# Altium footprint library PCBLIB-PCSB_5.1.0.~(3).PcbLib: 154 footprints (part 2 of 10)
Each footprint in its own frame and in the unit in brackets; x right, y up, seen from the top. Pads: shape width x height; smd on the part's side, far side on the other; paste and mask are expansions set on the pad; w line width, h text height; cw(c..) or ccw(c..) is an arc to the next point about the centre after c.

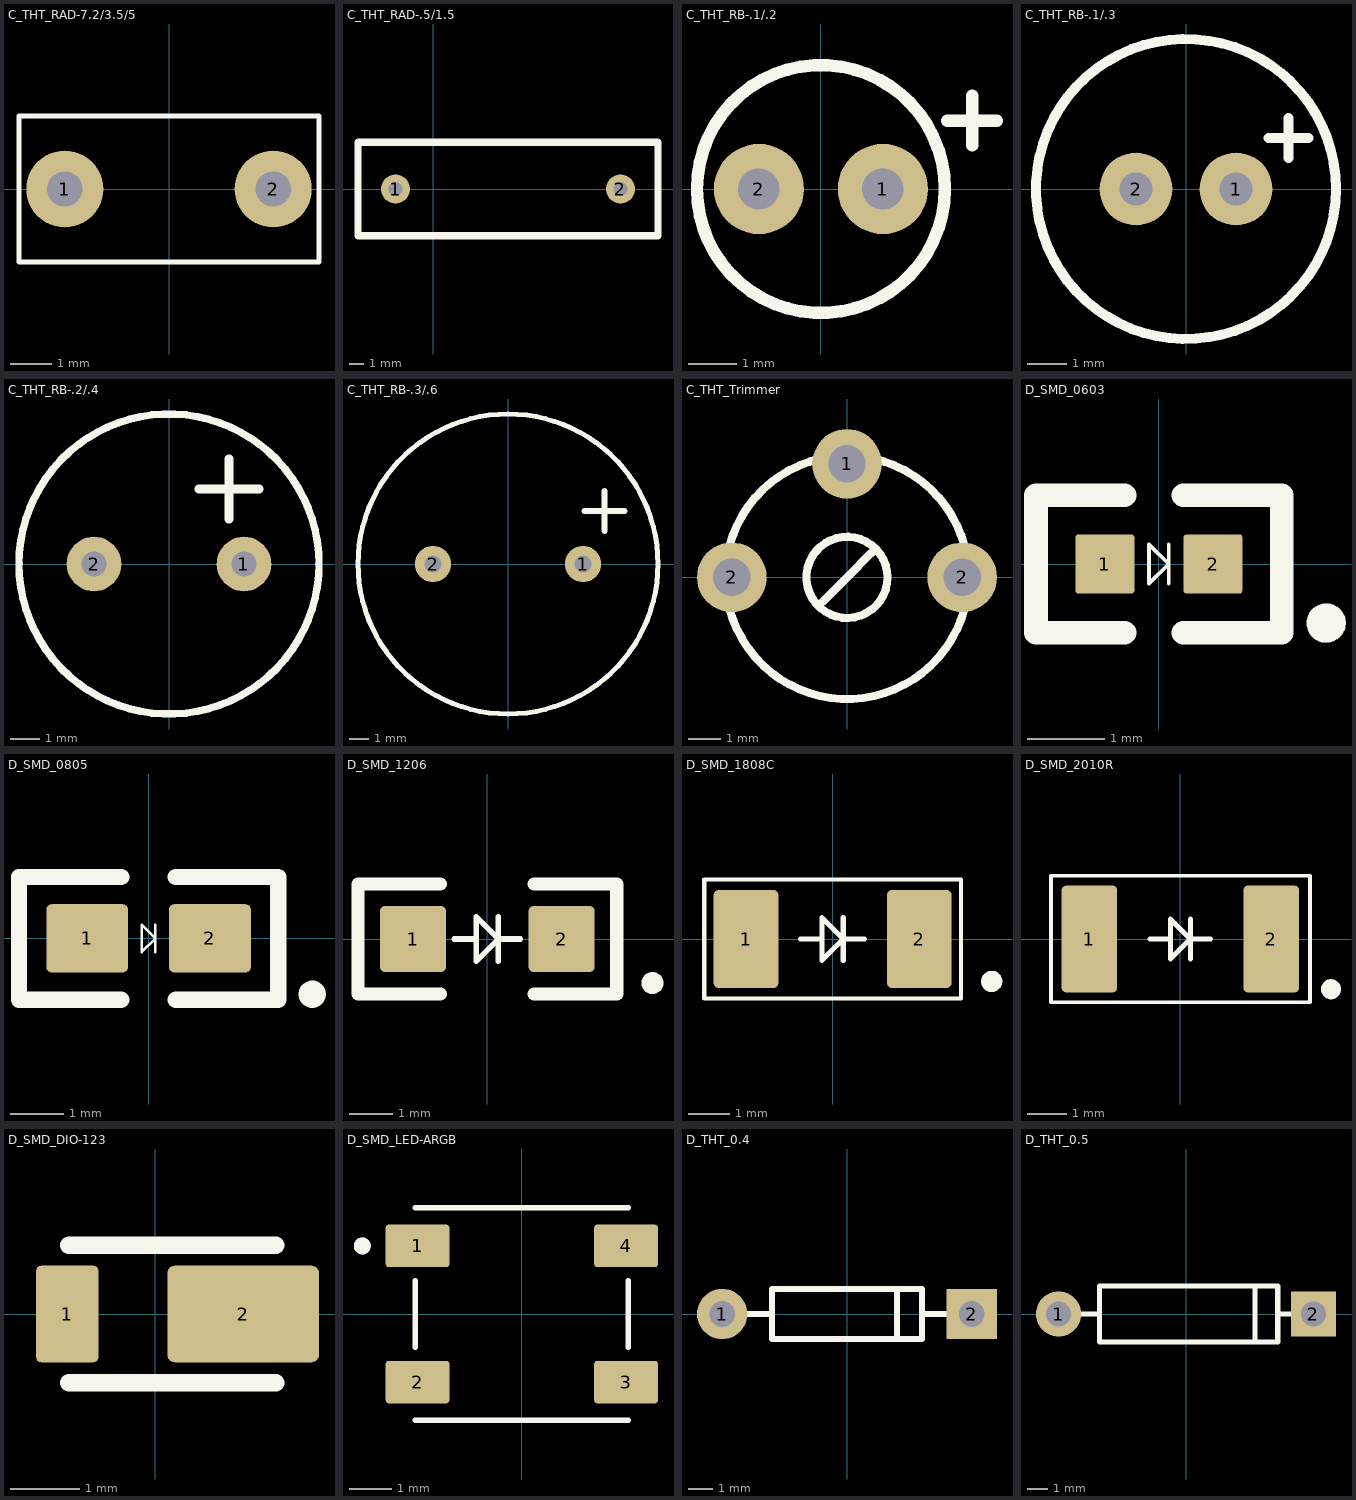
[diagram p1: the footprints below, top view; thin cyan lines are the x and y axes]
## C_THT_RAD-7.2/3.5/5 [mm] "LB-2024-04-17"
pads (2):
  round 1.85 hole 0.85: 1(-2.5,0) 2(2.5,0)
Top Overlay:
  lines w0.127: -3.6,-1.75 -3.6,1.75 3.6,1.75 3.6,-1.75 -3.6,-1.75

## C_THT_RAD-.5/1.5 [mm] "LB-2024-04-17"
pads (2):
  round 1.95 hole 0.95: 1(-2.54,0) 2(12.7,0)
Top Overlay:
  lines w0.5: -5.08,1.27 -5.08,3.175 15.24,3.175 15.24,-3.175 -5.08,-3.175 -5.08,1.595

## C_THT_RB-.1/.2 [mm] "LB-2024-04-15"
pads (2):
  round 1.85 hole 0.85: 1(1.27,0) 2(-1.27,0)
Top Overlay:
  circle w0.254: c0,0 r2.54
  lines w0.254: 2.592,1.4 3.608,1.4 ; 3.1,0.892 3.1,1.908

## C_THT_RB-.1/.3 [mm] "LB-2024-04-15"
pads (2):
  round 1.85 hole 0.85: 1(1.27,0) 2(-1.27,0)
Top Overlay:
  circle w0.254: c0,0 r3.81
  lines w0.254: 2.092,1.3 3.108,1.3 ; 2.6,0.792 2.6,1.808

## C_THT_RB-.2/.4 [mm] "LB-2024-04-16"
pads (2):
  round 1.85 hole 0.85: 1(2.54,0) 2(-2.54,0)
Top Overlay:
  circle w0.254: c0,0 r5.08
  lines w0.305: 1.016,2.54 3.048,2.54 ; 2.032,1.524 2.032,3.556

## C_THT_RB-.3/.6 [mm] "LB-2024-04-15"
pads (2):
  round 1.85 hole 0.85: 1(3.81,0) 2(-3.81,0)
Top Overlay:
  circle w0.254: c0,0 r7.62
  lines w0.305: 3.884,2.7 4.392,2.7 5.408,2.7 5.916,2.7 ; 4.9,1.684 4.9,2.192 4.9,3.208 4.9,3.716

## C_THT_Trimmer [mm] "LB-2024-04-19"
pads (3):
  round 2.15 hole 1.15: 1(0,3.5) 2(-3.55,0) 2(3.55,0)
Top Overlay:
  circle w0.254: c0,0 r1.25
  circle w0.254: c0,0 r3.75
  lines w0.254: -0.762,-0.762 0,0 0.762,0.762

## D_SMD_0603 [mil] "LB-2024-04-17"
pads (2):
  rrect10% 30x30 smd paste-0.79 mask+1.97: 1(-27.5,0) 2(27.5,0)
Top Overlay:
  circle w10: c85,-30 r5
  lines w1.97: -5,0 -5,10 ; 5,-10 5,10 5,0 ; -5,10 5,0 ; -5,10 -5,-10 5,0
  lines w12: -17.5,-35 -62.5,-35 -62.5,35 -17.5,35 ; 12.5,-35 62.5,-35 62.5,35 12.5,35

## D_SMD_0805 [mil] "LB-2024-04-17"
pads (2):
  rrect15% 60x50 smd paste-0.79 mask+1.97: 1(-45,0) 2(45,0)
Top Overlay:
  circle w10: c120,-41 r5
  lines w1.97: -5,0 -5,10 ; 5,-10 5,10 5,0 ; -5,10 5,0 ; -5,10 -5,-10 5,0
  lines w12: -20,-45 -95,-45 -95,45 -20,45 ; 20,-45 95,-45 95,45 20,45

## D_SMD_1206 [mil] "LB-2024-04-17"
pads (2):
  rrect15% 60x60 smd paste-0.79 mask+1.97: 1(-67.5,0) 2(67.5,0)
Top Overlay:
  circle w10: c150,-40 r5
  lines w5: -30,0 -10,0 ; 10,-20 10,20 ; 30,0 10,0 ; 10,0 -10,20 -10,-20 10,0
  lines w12: -42.5,-50 -117.5,-50 -117.5,50 -42.5,50 ; 42.5,-50 117.5,-50 117.5,50 42.5,50

## D_SMD_1808C [mm] "LB-2024-04-17"
height 2
pads (2):
  rrect15% 1.55x2.35 smd paste-0.02 mask+0.05: 1(-2.075,0) 2(2.075,0)
Top Overlay:
  circle w0.254: c3.81,-1.016 r0.127
  lines w0.1: -3.075,-1.425 -3.075,1.425 3.075,1.425 3.075,-1.425 -3.075,-1.425
  lines w0.127: -0.762,0 -0.254,0 ; 0.254,-0.508 0.254,0.508 ; 0.762,0 0.254,0 ; 0.254,0 -0.254,-0.508 -0.254,0.508 0.254,0

## D_SMD_2010R [mm] "LB-2024-04-17"
height 0.7
pads (2):
  rrect15% 1.4x2.7 smd paste-0.02 mask+0.05: 1(-2.3,0) 2(2.3,0)
Top Overlay:
  circle w0.254: c3.81,-1.27 r0.127
  lines w0.1: -3.275,-1.6 3.275,-1.6 3.275,1.6 -3.275,1.6 -3.275,-1.6
  lines w0.127: -0.762,0 -0.254,0 ; 0.254,-0.508 0.254,0.508 ; 0.762,0 0.254,0 ; 0.254,0 -0.254,-0.508 -0.254,0.508 0.254,0

## D_SMD_DIO-123 [mm] "LB-2024-04-25"
height 1
pads (2):
  rrect15% 0.9x1.4 smd paste-0.02 mask+0.05: 1(-1.275,0)
  rrect15% 2.2x1.4 smd paste-0.02 mask+0.05: 2(1.275,0)
Top Overlay:
  lines w0.254: -1.25,-1 1.75,-1 ; -1.25,1 1.75,1

## D_SMD_LED-ARGB [mm] "LB-2024-04-17"
pads (4):
  rrect15% 1.5x1 smd paste-0.02 mask+0.05: 1(-2.45,1.6) 2(-2.45,-1.6) 3(2.45,-1.6) 4(2.45,1.6)
Top Overlay:
  circle w0.2: c-3.75,1.6 r0.1
  lines w0.127: -2.5,-2.5 2.5,-2.5 ; -2.5,-0.787 -2.5,0.787 ; -2.5,2.5 2.5,2.5 ; 2.5,-0.787 2.5,0.787
Mechanical 13:
  circle w0.2: c-3.75,1.6 r0.1

## D_THT_0.4 [mm] "LB-2024-04-17"
pads (2):
  round 2.05 hole 1.05: 1(-5.08,0)
  rect 2.05x2.05 hole 1.05: 2(5.08,0)
Top Overlay:
  lines w0.254: -4.064,0 -3.048,0 ; 2.032,-1.016 2.032,1.016 ; 3.048,0 4.064,0 ; -3.048,-1.016 3.048,-1.016 3.048,1.016 -3.048,1.016 -3.048,-1.016

## D_THT_0.5 [mm] "LB-2024-04-17"
pads (2):
  round 2.25 hole 1.25: 1(-6.35,0)
  rect 2.25x2.25 hole 1.25: 2(6.35,0)
Top Overlay:
  lines w0.254: -5.334,0 -4.318,0 ; 3.429,-1.397 3.429,1.397 ; 4.699,0 5.715,0 ; -4.318,-1.397 -4.318,1.397 4.572,1.397 4.572,-1.397 -4.318,-1.397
